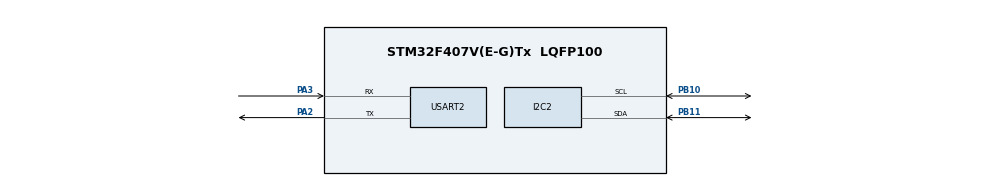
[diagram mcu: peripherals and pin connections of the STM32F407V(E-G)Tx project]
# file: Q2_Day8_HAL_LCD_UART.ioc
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Mcu.Family=STM32F4
Mcu.Name=STM32F407V(E-G)Tx
Mcu.Package=LQFP100
NVIC.PriorityGroup=NVIC_PRIORITYGROUP_0
PA2.Mode=Asynchronous
PA2.Signal=USART2_TX
PA3.Mode=Asynchronous
PA3.Signal=USART2_RX
PB10.Mode=I2C
PB10.Signal=I2C2_SCL
PB11.Mode=I2C
PB11.Signal=I2C2_SDA
ProjectManager.HeapSize=0x200
ProjectManager.StackSize=0x400
ProjectManager.TargetToolchain=STM32CubeIDE
RCC.48MHZClocksFreq_Value=14285714.285714285
RCC.AHBFreq_Value=25000000
RCC.APB1CLKDivider=RCC_HCLK_DIV4
RCC.APB1Freq_Value=6250000
RCC.APB1TimFreq_Value=12500000
RCC.APB2CLKDivider=RCC_HCLK_DIV2
RCC.APB2Freq_Value=12500000
RCC.APB2TimFreq_Value=25000000
RCC.CortexFreq_Value=25000000
RCC.HCLKFreq_Value=25000000
RCC.HSE_VALUE=8000000
RCC.HSI_VALUE=16000000
RCC.LSE_VALUE=32768
RCC.PLLM=8
RCC.PLLN=50
RCC.PLLP=RCC_PLLP_DIV4
RCC.PLLQ=7
RCC.SYSCLKFreq_VALUE=25000000
RCC.SYSCLKSource=RCC_SYSCLKSOURCE_PLLCLK
RCC.VCOOutputFreq_Value=100000000
USART2.VirtualMode=VM_ASYNC
board=STM32F407G-DISC1

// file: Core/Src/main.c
/* USER CODE BEGIN Header */
/**
  ******************************************************************************
  * @file           : main.c
  * @brief          : Main program body
  ******************************************************************************
  * @attention
  *
  * Copyright (c) 2026 STMicroelectronics.
  * All rights reserved.
  *
  * This software is licensed under terms that can be found in the LICENSE file
  * in the root directory of this software component.
  * If no LICENSE file comes with this software, it is provided AS-IS.
  *
  ******************************************************************************
  */
/* USER CODE END Header */
#include "main.h"
#include<lcd.h>
#include <string.h>

I2C_HandleTypeDef hi2c2;

UART_HandleTypeDef huart2;

void SystemClock_Config(void);
static void MX_GPIO_Init(void);
static void MX_I2C2_Init(void);
static void MX_USART2_UART_Init(void);
/* USER CODE BEGIN PFP */
void UART_Gets(char str[]) {
	char ch;
	for(int i=0; i<32; i++) {
		HAL_UART_Receive(&huart2, (uint8_t*)&ch, 1, HAL_MAX_DELAY);
		str[i] = ch;
		if(ch == '\r') {
			str[++i] = '\n';
			str[++i] = '\0';
			break;
		}
	}
}
/* USER CODE END PFP */

int main(void)
{

  /* MCU Configuration--------------------------------------------------------*/

  /* Reset of all peripherals, Initializes the Flash interface and the Systick. */
  HAL_Init();

  /* Configure the system clock */
  SystemClock_Config();
  lcd_init();

  /* Initialize all configured peripherals */
  MX_GPIO_Init();
  MX_I2C2_Init();
  MX_USART2_UART_Init();
  /* USER CODE BEGIN 2 */
  HAL_UART_Transmit(&huart2, (uint8_t*)"UART LCD\r\n", 13, HAL_MAX_DELAY);
  lcd_puts(LCD_LINE1, "Hello");
  /* USER CODE END 2 */

  /* Infinite loop */
  /* USER CODE BEGIN WHILE */
  while (1)
  {

	  char str[32];
	  	  // receive a string
	  	  HAL_UART_Transmit(&huart2, (uint8_t*)"Enter a string LINE1: \r\n", 26, HAL_MAX_DELAY);
	  	  UART_Gets(str);
	  	  // convert to capital case
	  	  strupr(str);
	  	  // transmit it back
	  	HAL_UART_Transmit(&huart2, (uint8_t*)str, strlen(str), HAL_MAX_DELAY);
	  	lcd_puts(LCD_LINE1, str);

	  	HAL_UART_Transmit(&huart2, (uint8_t*)"Enter a string LINE2: \r\n", 26, HAL_MAX_DELAY);
	  	UART_Gets(str);
	  		  	  // convert to capital case
	  	strupr(str);
	  	HAL_UART_Transmit(&huart2, (uint8_t*)str, strlen(str), HAL_MAX_DELAY);
	  	lcd_puts(LCD_LINE2, str);
    /* USER CODE END WHILE */

  }
}

void SystemClock_Config(void)
{
  RCC_OscInitTypeDef RCC_OscInitStruct = {0};
  RCC_ClkInitTypeDef RCC_ClkInitStruct = {0};

  /** Configure the main internal regulator output voltage
  */
  __HAL_RCC_PWR_CLK_ENABLE();
  __HAL_PWR_VOLTAGESCALING_CONFIG(PWR_REGULATOR_VOLTAGE_SCALE1);

  /** Initializes the RCC Oscillators according to the specified parameters
  * in the RCC_OscInitTypeDef structure.
  */
  RCC_OscInitStruct.OscillatorType = RCC_OSCILLATORTYPE_HSI;
  RCC_OscInitStruct.HSIState = RCC_HSI_ON;
  RCC_OscInitStruct.HSICalibrationValue = RCC_HSICALIBRATION_DEFAULT;
  RCC_OscInitStruct.PLL.PLLState = RCC_PLL_ON;
  RCC_OscInitStruct.PLL.PLLSource = RCC_PLLSOURCE_HSI;
  RCC_OscInitStruct.PLL.PLLM = 8;
  RCC_OscInitStruct.PLL.PLLN = 50;
  RCC_OscInitStruct.PLL.PLLP = RCC_PLLP_DIV2;
  RCC_OscInitStruct.PLL.PLLQ = 7;
  if (HAL_RCC_OscConfig(&RCC_OscInitStruct) != HAL_OK)
  {
    Error_Handler();
  }

  /** Initializes the CPU, AHB and APB buses clocks
  */
  RCC_ClkInitStruct.ClockType = RCC_CLOCKTYPE_HCLK|RCC_CLOCKTYPE_SYSCLK
                              |RCC_CLOCKTYPE_PCLK1|RCC_CLOCKTYPE_PCLK2;
  RCC_ClkInitStruct.SYSCLKSource = RCC_SYSCLKSOURCE_PLLCLK;
  RCC_ClkInitStruct.AHBCLKDivider = RCC_SYSCLK_DIV1;
  RCC_ClkInitStruct.APB1CLKDivider = RCC_HCLK_DIV4;
  RCC_ClkInitStruct.APB2CLKDivider = RCC_HCLK_DIV2;

  if (HAL_RCC_ClockConfig(&RCC_ClkInitStruct, FLASH_LATENCY_1) != HAL_OK)
  {
    Error_Handler();
  }
}

static void MX_I2C2_Init(void)
{

  hi2c2.Instance = I2C2;
  hi2c2.Init.ClockSpeed = 100000;
  hi2c2.Init.DutyCycle = I2C_DUTYCYCLE_2;
  hi2c2.Init.OwnAddress1 = 0;
  hi2c2.Init.AddressingMode = I2C_ADDRESSINGMODE_7BIT;
  hi2c2.Init.DualAddressMode = I2C_DUALADDRESS_DISABLE;
  hi2c2.Init.OwnAddress2 = 0;
  hi2c2.Init.GeneralCallMode = I2C_GENERALCALL_DISABLE;
  hi2c2.Init.NoStretchMode = I2C_NOSTRETCH_DISABLE;
  if (HAL_I2C_Init(&hi2c2) != HAL_OK)
  {
    Error_Handler();
  }

}

static void MX_USART2_UART_Init(void)
{

  huart2.Instance = USART2;
  huart2.Init.BaudRate = 115200;
  huart2.Init.WordLength = UART_WORDLENGTH_8B;
  huart2.Init.StopBits = UART_STOPBITS_1;
  huart2.Init.Parity = UART_PARITY_NONE;
  huart2.Init.Mode = UART_MODE_TX_RX;
  huart2.Init.HwFlowCtl = UART_HWCONTROL_NONE;
  huart2.Init.OverSampling = UART_OVERSAMPLING_16;
  if (HAL_UART_Init(&huart2) != HAL_OK)
  {
    Error_Handler();
  }

}

static void MX_GPIO_Init(void)
{

  /* GPIO Ports Clock Enable */
  __HAL_RCC_GPIOA_CLK_ENABLE();
  __HAL_RCC_GPIOB_CLK_ENABLE();

}

void Error_Handler(void)
{
  __disable_irq();
  while (1)
  {
  }
}
